VERSION 5.7 ;
DIVIDERCHAR "/" ;
BUSBITCHARS "[]" ;

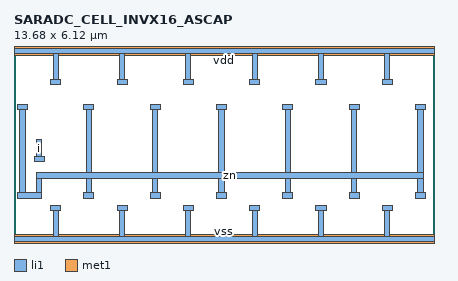
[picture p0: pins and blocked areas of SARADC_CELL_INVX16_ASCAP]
MACRO SARADC_CELL_INVX16_ASCAP
  CLASS BLOCK ;
  FOREIGN SARADC_CELL_INVX16_ASCAP ;
  ORIGIN 0.000 0.000 ;
  SIZE 13.680 BY 6.120 ;
  SYMMETRY X Y R90 ;
  PIN vnw
  END vnw
  PIN vpw
  END vpw
  PIN vdd
    DIRECTION INOUT ;
    USE POWER ;
    PORT
      LAYER li1 ;
        RECT 1.195 5.030 1.525 5.200 ;
        RECT 3.355 5.030 3.685 5.200 ;
        RECT 5.515 5.030 5.845 5.200 ;
        RECT 7.675 5.030 8.005 5.200 ;
        RECT 9.835 5.030 10.165 5.200 ;
        RECT 11.995 5.030 12.325 5.200 ;
        RECT 1.275 5.200 1.445 6.035 ;
        RECT 3.435 5.200 3.605 6.035 ;
        RECT 5.595 5.200 5.765 6.035 ;
        RECT 7.755 5.200 7.925 6.035 ;
        RECT 9.915 5.200 10.085 6.035 ;
        RECT 12.075 5.200 12.245 6.035 ;
        RECT 0.000 6.035 13.680 6.205 ;
      LAYER met1 ;
        RECT 0.000 5.985 13.680 6.255 ;
    END
  END vdd
  PIN vss
    DIRECTION INOUT ;
    USE GROUND ;
    PORT
      LAYER li1 ;
        RECT 0.000 -0.085 13.680 0.085 ;
        RECT 1.275 0.085 1.445 0.920 ;
        RECT 3.435 0.085 3.605 0.920 ;
        RECT 5.595 0.085 5.765 0.920 ;
        RECT 7.755 0.085 7.925 0.920 ;
        RECT 9.915 0.085 10.085 0.920 ;
        RECT 12.075 0.085 12.245 0.920 ;
        RECT 1.195 0.920 1.525 1.090 ;
        RECT 3.355 0.920 3.685 1.090 ;
        RECT 5.515 0.920 5.845 1.090 ;
        RECT 7.675 0.920 8.005 1.090 ;
        RECT 9.835 0.920 10.165 1.090 ;
        RECT 11.995 0.920 12.325 1.090 ;
      LAYER met1 ;
        RECT 0.000 -0.135 13.680 0.135 ;
    END
  END vss
  PIN i
    DIRECTION INOUT ;
    USE POWER ;
    PORT
      LAYER li1 ;
        RECT 0.655 2.520 0.985 2.690 ;
        RECT 0.735 2.690 0.905 3.230 ;
    END
  END i
  PIN zn
    DIRECTION INOUT ;
    USE POWER ;
    PORT
      LAYER li1 ;
        RECT 0.115 1.330 0.905 1.500 ;
        RECT 2.275 1.330 2.605 1.500 ;
        RECT 4.435 1.330 4.765 1.500 ;
        RECT 6.595 1.330 6.925 1.500 ;
        RECT 8.755 1.330 9.085 1.500 ;
        RECT 10.915 1.330 11.245 1.500 ;
        RECT 13.075 1.330 13.405 1.500 ;
        RECT 0.195 1.500 0.365 4.220 ;
        RECT 0.735 1.500 0.905 1.980 ;
        RECT 2.355 1.500 2.525 1.980 ;
        RECT 4.515 1.500 4.685 1.980 ;
        RECT 6.675 1.500 6.845 1.980 ;
        RECT 8.835 1.500 9.005 1.980 ;
        RECT 10.995 1.500 11.165 1.980 ;
        RECT 13.155 1.500 13.325 1.980 ;
        RECT 0.735 1.980 13.325 2.150 ;
        RECT 2.355 2.150 2.525 4.220 ;
        RECT 4.515 2.150 4.685 4.220 ;
        RECT 6.675 2.150 6.845 4.220 ;
        RECT 8.835 2.150 9.005 4.220 ;
        RECT 10.995 2.150 11.165 4.220 ;
        RECT 13.155 2.150 13.325 4.220 ;
        RECT 0.115 4.220 0.445 4.390 ;
        RECT 2.275 4.220 2.605 4.390 ;
        RECT 4.435 4.220 4.765 4.390 ;
        RECT 6.595 4.220 6.925 4.390 ;
        RECT 8.755 4.220 9.085 4.390 ;
        RECT 10.915 4.220 11.245 4.390 ;
        RECT 13.075 4.220 13.405 4.390 ;
    END
  END zn
END SARADC_CELL_INVX16_ASCAP

END LIBRARY
